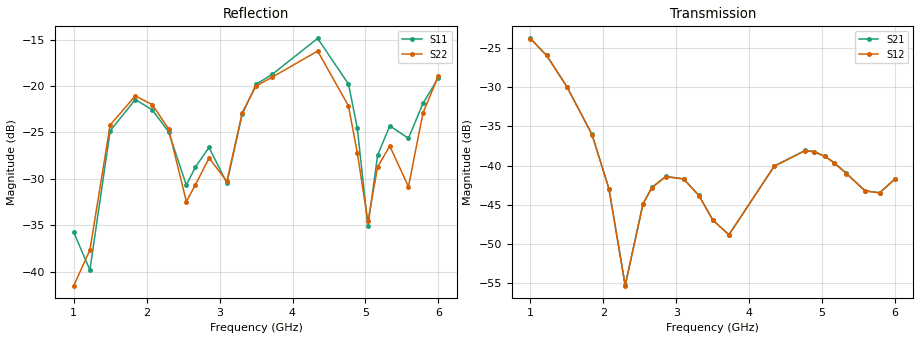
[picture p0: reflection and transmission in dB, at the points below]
!Agilent Technologies,E8364B,MY43040528,A.07.50.67
!Agilent E8364B: A.07.50.67
!Date: Sunday, March 01, 2026 21:06:51
!Correction: S11(Full 2 Port(1,2))
!S21(Full 2 Port(1,2))
!S12(Full 2 Port(1,2))
!S22(Full 2 Port(1,2))
!S2P File: Measurements: S11, S21, S12, S22:
# Hz S  dB  R 50
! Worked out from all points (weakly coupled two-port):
!   451 points, 1 GHz to 6 GHz, reference 50 ohm
!   highest |S21| = -23.78 dB at 1 GHz (marker M1); lowest = -55.3 dB at 2.3 GHz (marker M2)
!   lowest |S11| = -39.8 dB at 1.222 GHz (marker M3), VSWR 1.02, Z = 49.5 + j0.895 ohm
!   |S11| at or under -10 dB: start of sweep to end of sweep
!   |S22| runs from -42.8 to -15.9 dB; largest |S21 - S12| = 0.00025
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1e9  -35.76 58.4  -23.78 148.7  -23.82 148.7  -41.53 25.7
1.222222e9  -39.84 117.5  -25.93 20.4  -25.96 20.4  -37.69 96.8
1.5e9  -24.83 141.9  -29.92 -135.4  -29.94 -135.3  -24.20 75.3
1.844444e9  -21.45 81.8  -36.01 38.3  -36.03 38.3  -21.05 -4.9
2.077778e9  -22.57 53.1  -42.93 -84.7  -42.97 -84.8  -22.00 -48.3
2.3e9  -24.91 30.4  -55.25 -131.9  -55.28 -132.0  -24.60 -87.4
2.544444e9  -30.68 39.0  -44.85 160.4  -44.88 160.4  -32.45 -95.8
2.666667e9  -28.75 56.3  -42.77 96.1  -42.78 96.1  -30.68 -70.2
2.855556e9  -26.61 42.1  -41.37 -5.7  -41.40 -5.8  -27.76 -90.5
3.1e9  -30.46 57.7  -41.66 -138.8  -41.70 -138.8  -30.27 -81.3
3.311111e9  -23.02 71.2  -43.78 110.3  -43.81 110.3  -22.85 -86.8
3.5e9  -19.80 47.2  -46.88 22.6  -46.93 22.7  -19.99 -120.7
3.722222e9  -18.73 26.7  -48.80 -53.0  -48.80 -53.0  -19.03 -152.2
4.344444e9  -14.85 -44.5  -40.03 13.2  -40.07 13.2  -16.22 100.3
4.766667e9  -19.78 -110.0  -38.06 133.0  -38.09 133.1  -22.13 10.2
4.888889e9  -24.57 -126.3  -38.19 60.7  -38.23 60.8  -27.26 -10.5
5.033333e9  -35.14 -86.7  -38.77 -25.8  -38.80 -25.7  -34.59 23.7
5.166667e9  -27.44 -42.3  -39.62 -106.7  -39.66 -106.7  -28.71 41.2
5.333333e9  -24.29 -59.6  -40.97 148.7  -41.01 148.8  -26.46 10.8
5.588889e9  -25.63 -58.0  -43.20 -25.5  -43.22 -25.5  -30.85 15.9
5.788889e9  -21.85 -52.6  -43.43 -171.3  -43.47 -171.3  -22.88 16.8
6e9  -19.09 -70.2  -41.65 41.7  -41.69 41.7  -18.90 -23.0
